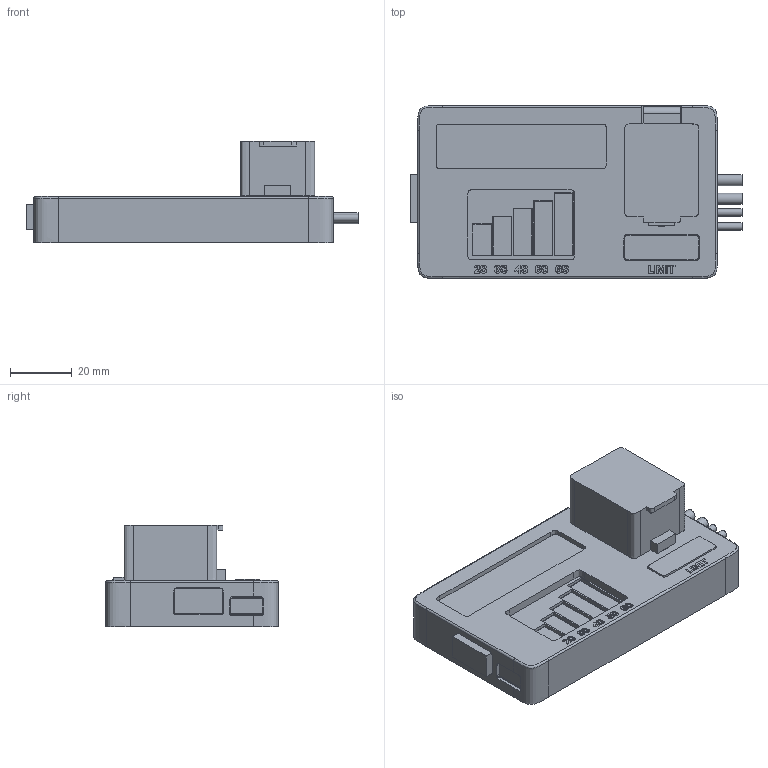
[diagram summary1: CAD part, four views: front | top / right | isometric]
STEP (ISO 10303-21) file: header records copied from the file, then geometry measured from it (millimetres).
FILE_DESCRIPTION(('Open CASCADE Model'),'2;1');
FILE_NAME('Open CASCADE Shape Model','2026-10-19T00:08:48',('Author'),( 'Open CASCADE'),'Open CASCADE STEP processor 7.9','Open CASCADE 7.9' ,'Unknown');
FILE_SCHEMA(('AUTOMOTIVE_DESIGN { 1 0 10303 214 1 1 1 1 }'));
Length unit declared in the file: millimetre
Products named in the file (213): smokebreak; top; bottom; guard; rocker; ring_inlay; text_inlay; pcb; display_module; SW1_bushing_lever; drone_leads; part_BZ1; part_C1; part_C10; part_C11; part_C12; part_C13; part_C14; part_C15; part_C16; part_C17; part_C18; part_C19; part_C2; part_C20; part_C21; part_C22; part_C23; part_C26; part_C27; part_C28; part_C29; part_C3; part_C30; part_C31; part_C32; part_C33; part_C34; part_C35; part_C36 ...
Assembly tree (212 placements, depth 2):
  smokebreak
    top
    bottom
    guard
    rocker
    ring_inlay
    text_inlay
    pcb
    display_module
    SW1_bushing_lever
    drone_leads
    part_BZ1
    part_C1
    part_C10
    part_C11
    part_C12
    part_C13
    part_C14
    part_C15
    part_C16
    part_C17
    part_C18
    part_C19
    part_C2
    part_C20
    part_C21
    part_C22
    part_C23
    part_C26
    part_C27
    part_C28
    part_C29
    part_C3
    part_C30
    part_C31
    part_C32
    part_C33
    part_C34
    part_C35
    part_C36
    part_C37
    part_C38
    part_C39
    part_C4
    part_C40
    part_C41
    part_C42
    part_C43
    part_C44
    part_C45
    part_C46
    part_C47
    part_C48
    part_C49
    part_C5
    part_C50
    part_C51
    part_C52
    part_C53
    part_C54
Bounding box: 107.5 x 56 x 32.9 mm (x, y, z)
Volume: 27558 mm3; surface area: 49178.3 mm2
Topology: 238 solids, 263 shells, 3779 faces, 9835 edges, 6574 vertices
Faces by surface type: plane 3648, cylinder 82, extrusion 38, bspline 6, sphere 4, cone 1
Full cylindrical faces by diameter (mm): 1.6 x2, 1.9 x3, 2.05 x1, 2.25 x2, 2.4 x4, 3 x2, 3.2 x3, 3.4 x3, 3.6 x4, 4 x3, 6.2 x3, 6.35 x1, 6.6 x1, 7.35 x1, 7.5 x3, 7.75 x1, 9 x4, 10 x4
Entity records: 267995 total; most frequent: CARTESIAN_POINT 64468, DIRECTION 36805, VECTOR 28525, LINE 28487, ORIENTED_EDGE 19375, PCURVE 19375, DEFINITIONAL_REPRESENTATION 19375, EDGE_CURVE 9823
